One B-rep face of a CAD part: STEP entity #1020.
In plain terms, the planar face has unit normal (1, 0, 0).
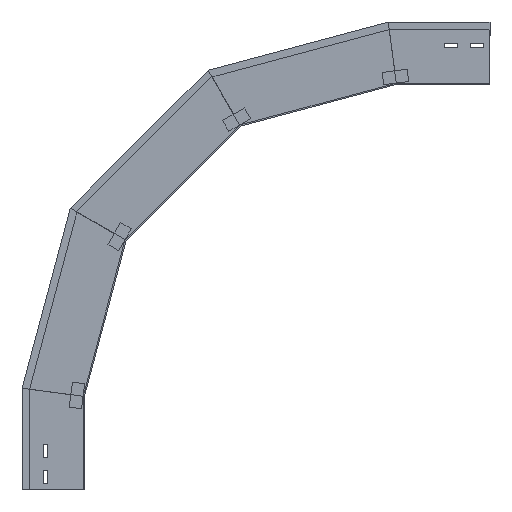
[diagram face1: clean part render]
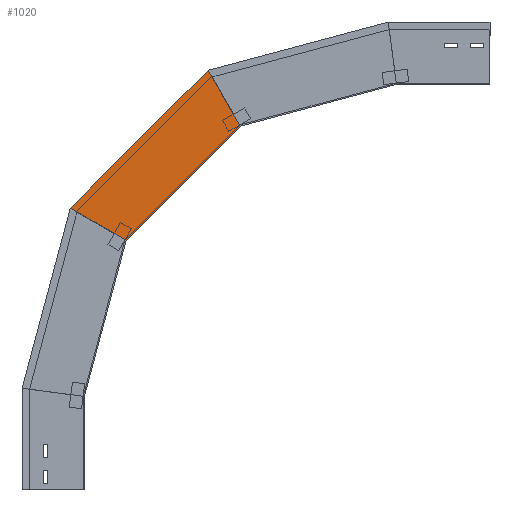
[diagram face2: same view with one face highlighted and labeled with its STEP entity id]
Its self-contained STEP definition (entity closure, numbers rounded to 3 decimals):
#24 = VERTEX_POINT ( 'NONE', #756 ) ;
#44 = LINE ( 'NONE', #1205, #1688 ) ;
#262 = DIRECTION ( 'NONE',  ( 0., -0.5, -0.866 ) ) ;
#272 = ORIENTED_EDGE ( 'NONE', *, *, #1803, .F. ) ;
#340 = DIRECTION ( 'NONE',  ( 0., -0.866, -0.5 ) ) ;
#367 = CARTESIAN_POINT ( 'NONE',  ( 0., -198.411, 672.973 ) ) ;
#403 = CARTESIAN_POINT ( 'NONE',  ( 0., -287.519, 518.633 ) ) ;
#470 = EDGE_CURVE ( 'NONE', #1888, #545, #1568, .T. ) ;
#545 = VERTEX_POINT ( 'NONE', #1695 ) ;
#549 = CARTESIAN_POINT ( 'NONE',  ( 0., 24.589, 449.973 ) ) ;
#556 = EDGE_LOOP ( 'NONE', ( #748, #1685, #704, #272 ) ) ;
#569 = VERTEX_POINT ( 'NONE', #955 ) ;
#607 = VECTOR ( 'NONE', #340, 1000. ) ;
#630 = VECTOR ( 'NONE', #262, 1000. ) ;
#704 = ORIENTED_EDGE ( 'NONE', *, *, #778, .F. ) ;
#748 = ORIENTED_EDGE ( 'NONE', *, *, #842, .T. ) ;
#756 = CARTESIAN_POINT ( 'NONE',  ( 0., -67.034, 400.175 ) ) ;
#761 = DIRECTION ( 'NONE',  ( 0., -0.707, 0.707 ) ) ;
#778 = EDGE_CURVE ( 'NONE', #24, #545, #44, .T. ) ;
#781 = CARTESIAN_POINT ( 'NONE',  ( 0., -128.356, 364.771 ) ) ;
#785 = VECTOR ( 'NONE', #1137, 1000. ) ;
#808 = DIRECTION ( 'NONE',  ( 1., 0., 0. ) ) ;
#842 = EDGE_CURVE ( 'NONE', #569, #1888, #1872, .T. ) ;
#924 = LINE ( 'NONE', #781, #607 ) ;
#955 = CARTESIAN_POINT ( 'NONE',  ( 0., 22.623, 451.939 ) ) ;
#1020 = ADVANCED_FACE ( 'NONE', ( #1379 ), #1232, .T. ) ;
#1137 = DIRECTION ( 'NONE',  ( 0., -0.707, 0.707 ) ) ;
#1205 = CARTESIAN_POINT ( 'NONE',  ( 0., -46.122, 379.263 ) ) ;
#1232 = PLANE ( 'NONE',  #1814 ) ;
#1379 = FACE_OUTER_BOUND ( 'NONE', #556, .T. ) ;
#1568 = LINE ( 'NONE', #403, #630 ) ;
#1681 = DIRECTION ( 'NONE',  ( 0., 0., -1. ) ) ;
#1685 = ORIENTED_EDGE ( 'NONE', *, *, #470, .T. ) ;
#1688 = VECTOR ( 'NONE', #761, 1000. ) ;
#1695 = CARTESIAN_POINT ( 'NONE',  ( 0., -250.175, 583.315 ) ) ;
#1803 = EDGE_CURVE ( 'NONE', #569, #24, #924, .T. ) ;
#1808 = CARTESIAN_POINT ( 'NONE',  ( 0., -46.122, 379.263 ) ) ;
#1814 = AXIS2_PLACEMENT_3D ( 'NONE', #1808, #808, #1681 ) ;
#1872 = LINE ( 'NONE', #549, #785 ) ;
#1888 = VERTEX_POINT ( 'NONE', #367 ) ;
